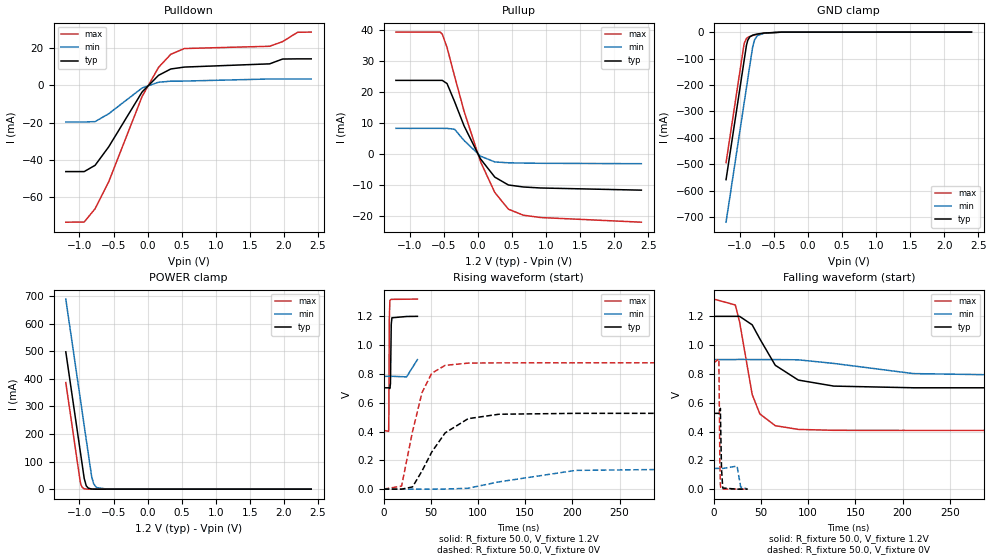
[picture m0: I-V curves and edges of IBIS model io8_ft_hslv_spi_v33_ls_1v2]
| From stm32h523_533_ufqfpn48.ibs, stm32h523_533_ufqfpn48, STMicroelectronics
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[Model]   io8_ft_hslv_spi_v33_ls_1v2
Model_type I/O
Polarity   Non-Inverting
Enable   Active-Low
| CAP_THRESHOLD on pad IOFT is "UDTCAPC" :
| Rising=20.0% of vddiom   Falling=80.0% of vddiom
| C_comp min and max val. don't necessarily correlate with the min and max pvt
| but are the smallest and greatest pad capacitance found.
| var   typ   min   max
C_comp   3.39565pF  3.37225pF  3.42675pF
|C_comp_pullup   2.09370pF  2.00525pF  1.90830pF
|C_comp_pulldown   1.30195pF  1.36700pF  1.51845pF
Vinl = 270.0mV
Vinh = 924.0mV
Vmeas = 600.0mV   | Reference voltage for timing measurements
Cref  = 50.0pF   | Timing specification test load capacitance value
Rref  = 100.0MOhm   | Timing specification test load resistance value
Vref  = 600.0mV   | Timing specification test load voltage
[Model Spec]
| TIME_THRESHOLD on pin ZIV33M is "CMOS" :
| Rising=40.0% of vddiom   Falling=60.0% of vddiom
Vinl 437.80000mV 335.80000mV 479.80000mV
Vinh 728.20000mV 529.20000mV 807.20000mV
| variable   typ   min   max
[Temperature Range] 25.0 125.0 -40.0
| variable   typ   min   max
[Voltage Range] 1.2V 900.0mV 1.32V
| variable   typ   min   max
[POWER Clamp Reference] 1.2V 900.0mV 1.32V
| variable   typ   min   max
[GND Clamp Reference] 0V 0V 0V
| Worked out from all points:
|   slope of the pulldown table from 0 to 0.18 V, typ, clamps not added: 30.6 ohm
|   slope of the pullup table from 0 to 0.18 V, typ, clamps not added: 31.2 ohm
|   GND clamp passes 1 mA (typ) near -0.52 V on its own axis
|   POWER clamp passes 1 mA (typ) near -0.84 V on its own axis
|   rising waveform, R_fixture 50.0, V_fixture 1.2V: 20-80 % time 521ps typ, 1.45ns min, 318ps max; typ from 0.704 V to 1.2 V
|   falling waveform, R_fixture 50.0, V_fixture 1.2V: 20-80 % time 31.2ns typ, 76ns min, 16.2ns max; typ from 1.2 V to 0.704 V
|   rising waveform, R_fixture 50.0, V_fixture 0V: 20-80 % time 31.4ns typ, 67.4ns min, 18.5ns max; typ from 0 V to 0.527 V
|   falling waveform, R_fixture 50.0, V_fixture 0V: 20-80 % time 1.08ns typ, 2.12ns min, 798ps max; typ from 0.527 V to 0 V
[POWER Clamp]
-1.2V     497.8mA    689.2mA    386.5mA
-990mV    140.8mA    332.2mA    29.53mA
-980mV    123.8mA    315.2mA    17.95mA
-960mV    89.81mA    281.2mA    6.634mA
-930mV    38.81mA    230.2mA    1.49mA
-900mV    12.07mA    179.2mA    334.8uA
-870mV    3.756mA    128.2mA    75.22uA
-820mV    536.4uA    44.98mA    6.246uA
-790mV    166.9uA    18.76mA    1.403uA
-750mV    35.18uA    5.846mA    191.8nA
-590mV    70.08nA    55uA       163.4pA
2.4V      0A         0A         0A
[GND Clamp]
-1.2V     -558.2mA   -719mA     -494.1mA
-940mV    -116.2mA   -277mA     -52.06mA
-930mV    -99.19mA   -260mA     -39.94mA
-900mV    -49.1mA    -209mA     -23.76mA
-880mV    -30.14mA   -175mA     -19.6mA
-850mV    -17.82mA   -124mA     -16.09mA
-810mV    -11.73mA   -56.78mA   -12.91mA
-780mV    -9.444mA   -28.21mA   -10.92mA
-740mV    -7.291mA   -13.16mA   -8.574mA
-640mV    -3.573mA   -4.171mA   -3.954mA
-380mV    -61.75uA   -230.3uA   -20.32uA
2.4V      3.863nA    718.4nA    150.6pA
| variable   typ   min   max
[Pullup Reference] 1.2V 900.0mV 1.32V
| variable   typ   min   max
[Pulldown Reference] 0V 0V 0V
[Pullup]
-1.2V     23.71mA    8.291mA    39.22mA
-550mV    23.71mA    8.291mA    39.22mA
-520mV    23.71mA    8.291mA    38.56mA
-450mV    22.68mA    8.291mA    34.27mA
-340mV    16.91mA    8.022mA    25.08mA
-200mV    9.076mA    4.391mA    13.76mA
40mV      -1.483mA   -616.8uA   -2.356mA
250mV     -7.358mA   -2.482mA   -12.29mA
450mV     -9.893mA   -2.768mA   -17.67mA
670mV     -10.53mA   -2.855mA   -19.6mA
920mV     -10.85mA   -2.921mA   -20.34mA
2.4V      -11.55mA   -3.055mA   -21.84mA
[Pulldown]
-1.2V     -46.17mA   -19.62mA   -73.27mA
-930mV    -46.17mA   -19.62mA   -73.18mA
-770mV    -42.8mA    -19.4mA    -66.04mA
-570mV    -32.88mA   -15.18mA   -51.58mA
-80mV     -3.488mA   -1.363mA   -5.887mA
160mV     5.368mA    1.685mA    9.621mA
340mV     8.782mA    2.25mA     16.66mA
540mV     9.805mA    2.305mA    19.74mA
1.79V     11.53mA    3.427mA    20.94mA
1.98V     14.11mA    3.427mA    23.43mA
2.2V      14.2mA     3.427mA    28.44mA
2.4V      14.2mA     3.427mA    28.54mA
[Ramp]
dV/dt_r 315.91002mV/31.04194ns 86.26236mV/66.98952ns 526.33105mV/18.03082ns
dV/dt_f 297.8048mV/30.79769ns 69.47263mV/75.54312ns 547.13927mV/15.81751ns
R_load = 50.0
| Removed startup time: 0s 0s 0s  .
| Removed end time: 35.75ns.
[Rising Waveform]
R_fixture   = 50.0
V_fixture   = 1.2V
V_fixture_min = 900.0mV
V_fixture_max = 1.32V
0s        703.7mV    783.5mV    408.1mV
5.3ns     703.7mV    783.5mV    401.4mV
5.55ns    703.7mV    783.5mV    527.3mV
5.95ns    703.7mV    783.5mV    1.17V
6.6ns     699mV      783.5mV    1.308V
7.2ns     732.2mV    783.5mV    1.315V
8.05ns    1.144V     783.5mV    1.318V
8.75ns    1.19V      783.5mV    1.318V
24.3ns    1.199V     779.7mV    1.319V
35.75ns   1.2V       899.3mV    1.32V
| Removed startup time: 0s 0s 0s  .
| Removed end time: 398.75ns.
[Falling Waveform]
R_fixture   = 50.0
V_fixture   = 1.2V
V_fixture_min = 900.0mV
V_fixture_max = 1.32V
0s        1.2V       900mV      1.32V
22.8ns    1.2V       900mV      1.279V
27.35ns   1.2V       901.1mV    1.161V
40.7ns    1.141V     899.9mV    657mV
48.85ns   1.043V     900mV      522.3mV
65.1ns    860.5mV    900mV      441.1mV
89.55ns   757.6mV    898.2mV    415mV
127.2ns   715.7mV    873.1mV    408.8mV
211.6ns   704.1mV    802.5mV    408.1mV
398.8ns   703.7mV    784.2mV    408.1mV
| Removed startup time: 0s 0s 0s  .
| Removed end time: 398.7ns.
[Rising Waveform]
R_fixture   = 50.0
V_fixture   = 0V
V_fixture_min = 0V
V_fixture_max = 0V
0s        179.6nV    692.8nV    121.7nV
19ns      -243.3uV   901.8nV    20.92mV
30.6ns    15.38mV    -103.8uV   400.3mV
40.7ns    126.9mV    -75.14uV   671.6mV
50.9ns    257.2mV    -20.45uV   804.5mV
65.1ns    390.4mV    448.8uV    859.5mV
89.5ns    489.4mV    6.187mV    875.2mV
122.1ns   520.1mV    50.45mV    877mV
203.5ns   526.3mV    130.1mV    877.2mV
398.7ns   526.5mV    143.8mV    877.2mV
| Removed startup time: 0s 0s 0s  .
| Removed end time: 35.75ns.
[Falling Waveform]
R_fixture   = 50.0
V_fixture   = 0V
V_fixture_min = 0V
V_fixture_max = 0V
0s        526.6mV    144.1mV    877.3mV
5.4ns     526.7mV    144.1mV    904.1mV
6.45ns    526.7mV    144.1mV    174.1mV
7ns       561mV      144.1mV    29.46mV
7.35ns    417.4mV    144.1mV    11.9mV
8.2ns     142.8mV    144.1mV    2.153mV
9.5ns     8.298mV    144.1mV    1.016mV
24.7ns    308.6uV    160.4mV    450.9uV
28.5ns    357uV      15.92mV    384.8uV
35.75ns   287.5uV    1.255mV    173uV
